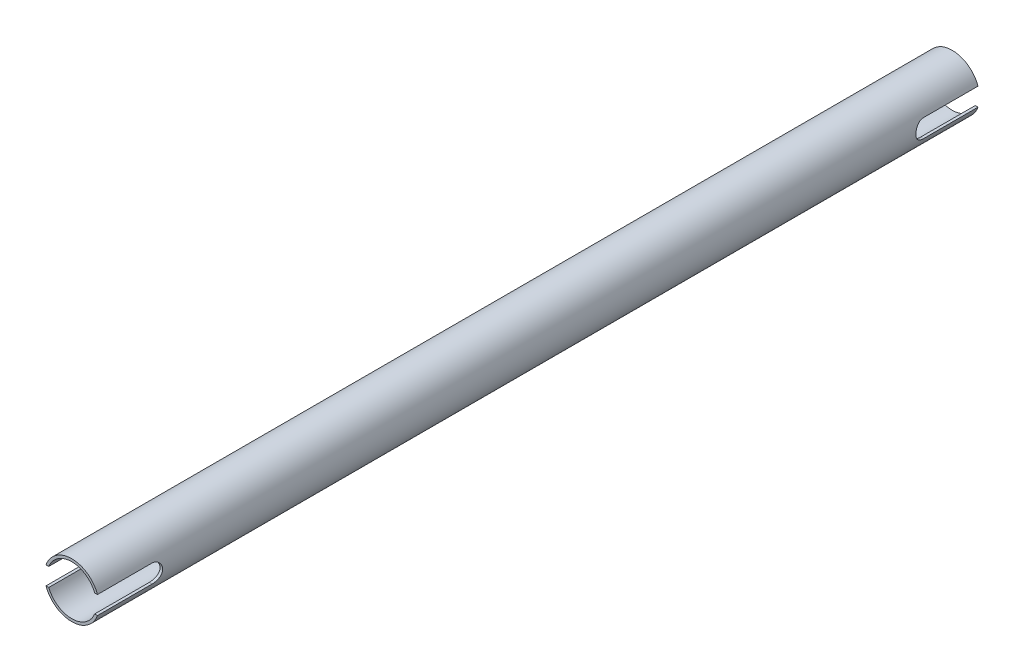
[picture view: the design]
ISO-10303-21;
HEADER;
FILE_DESCRIPTION(('STEP AP214'),'2;1');
FILE_NAME('part.step','',(''),(''),'','','');
FILE_SCHEMA(('AUTOMOTIVE_DESIGN { 1 0 10303 214 1 1 1 1 }'));
ENDSEC;
DATA;
#1=APPLICATION_CONTEXT('core data for automotive mechanical design processes');
#2=APPLICATION_PROTOCOL_DEFINITION('international standard','automotive_design',2000,#1);
#3=PRODUCT_CONTEXT('',#1,'mechanical');
#4=PRODUCT('Part','Part','',(#3));
#5=PRODUCT_RELATED_PRODUCT_CATEGORY('part','',(#4));
#6=PRODUCT_DEFINITION_FORMATION('','',#4);
#7=PRODUCT_DEFINITION_CONTEXT('part definition',#1,'design');
#8=PRODUCT_DEFINITION('design','',#6,#7);
#9=PRODUCT_DEFINITION_SHAPE('','',#8);
#10=(LENGTH_UNIT() NAMED_UNIT(*) SI_UNIT(.MILLI.,.METRE.));
#11=(NAMED_UNIT(*) PLANE_ANGLE_UNIT() SI_UNIT($,.RADIAN.));
#12=(NAMED_UNIT(*) SI_UNIT($,.STERADIAN.) SOLID_ANGLE_UNIT());
#13=UNCERTAINTY_MEASURE_WITH_UNIT(LENGTH_MEASURE(1.E-05),#10,'distance_accuracy_value','');
#14=(GEOMETRIC_REPRESENTATION_CONTEXT(3) GLOBAL_UNCERTAINTY_ASSIGNED_CONTEXT((#13)) GLOBAL_UNIT_ASSIGNED_CONTEXT((#10,
#11,#12)) REPRESENTATION_CONTEXT('',''));
#15=CARTESIAN_POINT('',(0.,0.,0.));
#16=DIRECTION('',(0.,0.,1.));
#17=DIRECTION('',(1.,0.,0.));
#18=AXIS2_PLACEMENT_3D('',#15,#16,#17);
#19=CARTESIAN_POINT('',(0.,0.,-153.697183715));
#20=DIRECTION('',(0.,0.,1.));
#21=DIRECTION('',(1.,0.,0.));
#22=AXIS2_PLACEMENT_3D('',#19,#20,#21);
#23=PLANE('',#22);
#24=DIRECTION('',(1.,0.,0.));
#25=VECTOR('',#24,1.);
#26=CARTESIAN_POINT('',(-9.525,3.17499999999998,-153.697183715));
#27=LINE('',#26,#25);
#28=CARTESIAN_POINT('',(-8.98025612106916,3.17499999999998,-153.697183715));
#29=VERTEX_POINT('',#28);
#30=CARTESIAN_POINT('',(-8.00659451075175,3.17499999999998,-153.697183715));
#31=VERTEX_POINT('',#30);
#32=EDGE_CURVE('E178',#29,#31,#27,.T.);
#33=ORIENTED_EDGE('',*,*,#32,.F.);
#34=CARTESIAN_POINT('',(0.,0.,-153.697183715));
#35=DIRECTION('',(0.,0.,1.));
#36=DIRECTION('',(1.,0.,0.));
#37=AXIS2_PLACEMENT_3D('',#34,#35,#36);
#38=CIRCLE('',#37,9.525);
#39=CARTESIAN_POINT('',(8.98025612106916,3.17499999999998,-153.697183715));
#40=VERTEX_POINT('',#39);
#41=EDGE_CURVE('E281',#40,#29,#38,.T.);
#42=ORIENTED_EDGE('',*,*,#41,.F.);
#43=CARTESIAN_POINT('',(8.00659451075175,3.17499999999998,-153.697183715));
#44=VERTEX_POINT('',#43);
#45=EDGE_CURVE('E344',#44,#40,#27,.T.);
#46=ORIENTED_EDGE('',*,*,#45,.F.);
#47=CARTESIAN_POINT('',(0.,0.,-153.697183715));
#48=DIRECTION('',(0.,0.,1.));
#49=DIRECTION('',(1.,0.,0.));
#50=AXIS2_PLACEMENT_3D('',#47,#48,#49);
#51=CIRCLE('',#50,8.61314);
#52=EDGE_CURVE('E272',#44,#31,#51,.T.);
#53=ORIENTED_EDGE('',*,*,#52,.T.);
#54=EDGE_LOOP('',(#33,#42,#46,#53));
#55=FACE_BOUND('',#54,.T.);
#56=ADVANCED_FACE('F40',(#55),#23,.F.);
#57=DIRECTION('',(1.,0.,0.));
#58=VECTOR('',#57,1.);
#59=CARTESIAN_POINT('',(-9.525,-3.17500000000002,-153.697183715));
#60=LINE('',#59,#58);
#61=CARTESIAN_POINT('',(8.00659451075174,-3.17500000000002,-153.697183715));
#62=VERTEX_POINT('',#61);
#63=CARTESIAN_POINT('',(8.98025612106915,-3.17500000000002,-153.697183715));
#64=VERTEX_POINT('',#63);
#65=EDGE_CURVE('E171',#62,#64,#60,.T.);
#66=ORIENTED_EDGE('',*,*,#65,.T.);
#67=CARTESIAN_POINT('',(-8.98025612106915,-3.17500000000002,-153.697183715));
#68=VERTEX_POINT('',#67);
#69=EDGE_CURVE('E279',#68,#64,#38,.T.);
#70=ORIENTED_EDGE('',*,*,#69,.F.);
#71=CARTESIAN_POINT('',(-8.00659451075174,-3.17500000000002,-153.697183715));
#72=VERTEX_POINT('',#71);
#73=EDGE_CURVE('E160',#68,#72,#60,.T.);
#74=ORIENTED_EDGE('',*,*,#73,.T.);
#75=EDGE_CURVE('E271',#72,#62,#51,.T.);
#76=ORIENTED_EDGE('',*,*,#75,.T.);
#77=EDGE_LOOP('',(#66,#70,#74,#76));
#78=FACE_BOUND('',#77,.T.);
#79=ADVANCED_FACE('F341',(#78),#23,.F.);
#80=CARTESIAN_POINT('',(0.,0.,153.697183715));
#81=DIRECTION('',(0.,0.,-1.));
#82=DIRECTION('',(-1.,0.,0.));
#83=AXIS2_PLACEMENT_3D('',#80,#81,#82);
#84=CYLINDRICAL_SURFACE('',#83,9.525);
#85=CARTESIAN_POINT('',(0.,0.,153.697183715));
#86=DIRECTION('',(0.,0.,1.));
#87=DIRECTION('',(1.,0.,0.));
#88=AXIS2_PLACEMENT_3D('',#85,#86,#87);
#89=CIRCLE('',#88,9.525);
#90=CARTESIAN_POINT('',(8.98025612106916,3.17499999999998,153.697183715));
#91=VERTEX_POINT('',#90);
#92=CARTESIAN_POINT('',(-8.98025612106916,3.17499999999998,153.697183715));
#93=VERTEX_POINT('',#92);
#94=EDGE_CURVE('E284',#91,#93,#89,.T.);
#95=ORIENTED_EDGE('',*,*,#94,.F.);
#96=DIRECTION('',(0.,0.,-1.));
#97=VECTOR('',#96,1.);
#98=CARTESIAN_POINT('',(8.98025612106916,3.17499999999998,153.697183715));
#99=LINE('',#98,#97);
#100=CARTESIAN_POINT('',(8.98025612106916,3.17499999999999,134.647183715));
#101=VERTEX_POINT('',#100);
#102=EDGE_CURVE('E268',#91,#101,#99,.T.);
#103=ORIENTED_EDGE('',*,*,#102,.T.);
#104=CARTESIAN_POINT('',(8.98025612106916,3.17499999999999,134.647183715));
#105=CARTESIAN_POINT('',(8.9802423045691,3.17501141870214,134.560560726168));
#106=CARTESIAN_POINT('',(8.98150913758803,3.17145526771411,134.473945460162));
#107=CARTESIAN_POINT('',(8.9865012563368,3.15729678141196,134.301386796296));
#108=CARTESIAN_POINT('',(8.99022587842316,3.14669634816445,134.215443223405));
#109=CARTESIAN_POINT('',(9.00001635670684,3.11857973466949,134.04508879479));
#110=CARTESIAN_POINT('',(9.00607526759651,3.1010840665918,133.96067416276));
#111=CARTESIAN_POINT('',(9.02033527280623,3.05935609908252,133.7937332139));
#112=CARTESIAN_POINT('',(9.02853644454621,3.03512355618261,133.711206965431));
#113=CARTESIAN_POINT('',(9.05598824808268,2.95264270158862,133.467402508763));
#114=CARTESIAN_POINT('',(9.07810279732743,2.8845689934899,133.309646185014));
#115=CARTESIAN_POINT('',(9.12745233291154,2.72437585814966,133.00777016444));
#116=CARTESIAN_POINT('',(9.15469046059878,2.63224166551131,132.863658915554));
#117=CARTESIAN_POINT('',(9.21240451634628,2.42269004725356,132.587506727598));
#118=CARTESIAN_POINT('',(9.24296080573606,2.30449481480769,132.456071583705));
#119=CARTESIAN_POINT('',(9.30318975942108,2.04783780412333,132.214476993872));
#120=CARTESIAN_POINT('',(9.33286226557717,1.90937242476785,132.104321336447));
#121=CARTESIAN_POINT('',(9.38891576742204,1.61164171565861,131.905636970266));
#122=CARTESIAN_POINT('',(9.41519063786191,1.4519278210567,131.817747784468));
#123=CARTESIAN_POINT('',(9.46053507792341,1.11896283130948,131.670328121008));
#124=CARTESIAN_POINT('',(9.47960684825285,0.945715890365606,131.610788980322));
#125=CARTESIAN_POINT('',(9.50782550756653,0.596993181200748,131.523822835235));
#126=CARTESIAN_POINT('',(9.5172945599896,0.421804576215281,131.49535084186));
#127=CARTESIAN_POINT('',(9.52638456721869,0.068894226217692,131.468004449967));
#128=CARTESIAN_POINT('',(9.52600786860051,-0.108826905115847,131.46912299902));
#129=CARTESIAN_POINT('',(9.515666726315,-0.454354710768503,131.500264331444));
#130=CARTESIAN_POINT('',(9.50607893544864,-0.622276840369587,131.529151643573));
#131=CARTESIAN_POINT('',(9.47886599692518,-0.950734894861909,131.613132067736));
#132=CARTESIAN_POINT('',(9.4612404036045,-1.11127040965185,131.668226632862));
#133=CARTESIAN_POINT('',(9.41945246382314,-1.42288461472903,131.803721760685));
#134=CARTESIAN_POINT('',(9.39520718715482,-1.57381114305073,131.884445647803));
#135=CARTESIAN_POINT('',(9.34270382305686,-1.86031043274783,132.068638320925));
#136=CARTESIAN_POINT('',(9.31444464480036,-1.99587900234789,132.172113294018));
#137=CARTESIAN_POINT('',(9.25532407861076,-2.25455959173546,132.404592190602));
#138=CARTESIAN_POINT('',(9.22440281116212,-2.37678676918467,132.534567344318));
#139=CARTESIAN_POINT('',(9.16455803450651,-2.59801162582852,132.813424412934));
#140=CARTESIAN_POINT('',(9.13563517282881,-2.697001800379,132.962312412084));
#141=CARTESIAN_POINT('',(9.08272269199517,-2.87021834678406,133.277785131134));
#142=CARTESIAN_POINT('',(9.05881220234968,-2.94405757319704,133.444598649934));
#143=CARTESIAN_POINT('',(9.02936653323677,-3.03267330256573,133.702816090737));
#144=CARTESIAN_POINT('',(9.02062228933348,-3.05851877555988,133.790205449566));
#145=CARTESIAN_POINT('',(9.00554368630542,-3.10263697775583,133.967067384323));
#146=CARTESIAN_POINT('',(8.99920822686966,-3.12091316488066,134.056538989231));
#147=CARTESIAN_POINT('',(8.989590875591,-3.14850521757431,134.229388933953));
#148=CARTESIAN_POINT('',(8.98609952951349,-3.15843785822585,134.312658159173));
#149=CARTESIAN_POINT('',(8.98142776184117,-3.1716856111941,134.479676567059));
#150=CARTESIAN_POINT('',(8.98024435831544,-3.17500926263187,134.563424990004));
#151=CARTESIAN_POINT('',(8.98025612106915,-3.17500000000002,134.647183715));
#152=B_SPLINE_CURVE_WITH_KNOTS('',3,(#104,#105,#106,#107,#108,#109,#110,#111,#112,#113,#114,
#115,#116,#117,#118,#119,#120,#121,#122,#123,#124,#125,#126,#127,#128,#129,#130,#131,#132,#133,
#134,#135,#136,#137,#138,#139,#140,#141,#142,#143,#144,#145,#146,#147,#148,#149,#150,#151),
.UNSPECIFIED.,.F.,.F.,(4,2,2,2,2,2,2,2,2,2,2,2,2,2,2,2,2,2,2,2,2,2,2,4),(0.,0.259773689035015,
0.519477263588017,0.77841402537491,1.03736014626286,1.55449291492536,2.07194378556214,
2.60766387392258,3.14347925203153,3.69327981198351,4.24291225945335,4.77342553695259,
5.30381237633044,5.81339512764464,6.32300613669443,6.83932018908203,7.35577482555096,
7.89650105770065,8.43740168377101,8.98628729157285,9.26063415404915,9.53485554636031,
9.78636405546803,10.0375473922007),.UNSPECIFIED.);
#153=CARTESIAN_POINT('',(8.98025612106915,-3.17500000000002,134.647183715));
#154=VERTEX_POINT('',#153);
#155=EDGE_CURVE('E258',#101,#154,#152,.T.);
#156=ORIENTED_EDGE('',*,*,#155,.T.);
#157=DIRECTION('',(0.,0.,-1.));
#158=VECTOR('',#157,1.);
#159=CARTESIAN_POINT('',(8.98025612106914,-3.17500000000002,153.697183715));
#160=LINE('',#159,#158);
#161=CARTESIAN_POINT('',(8.98025612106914,-3.17500000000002,153.697183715));
#162=VERTEX_POINT('',#161);
#163=EDGE_CURVE('E312',#154,#162,#160,.F.);
#164=ORIENTED_EDGE('',*,*,#163,.T.);
#165=CARTESIAN_POINT('',(-8.98025612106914,-3.17500000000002,153.697183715));
#166=VERTEX_POINT('',#165);
#167=EDGE_CURVE('E282',#166,#162,#89,.T.);
#168=ORIENTED_EDGE('',*,*,#167,.F.);
#169=DIRECTION('',(0.,0.,-1.));
#170=VECTOR('',#169,1.);
#171=CARTESIAN_POINT('',(-8.98025612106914,-3.17500000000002,153.697183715));
#172=LINE('',#171,#170);
#173=CARTESIAN_POINT('',(-8.98025612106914,-3.17500000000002,134.647183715));
#174=VERTEX_POINT('',#173);
#175=EDGE_CURVE('E259',#166,#174,#172,.T.);
#176=ORIENTED_EDGE('',*,*,#175,.T.);
#177=CARTESIAN_POINT('',(-8.98025612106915,-3.17500000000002,134.647183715));
#178=CARTESIAN_POINT('',(-8.98024230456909,-3.17501141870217,134.560560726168));
#179=CARTESIAN_POINT('',(-8.98150913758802,-3.17145526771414,134.473945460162));
#180=CARTESIAN_POINT('',(-8.98650125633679,-3.15729678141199,134.301386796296));
#181=CARTESIAN_POINT('',(-8.99022587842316,-3.14669634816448,134.215443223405));
#182=CARTESIAN_POINT('',(-9.00001635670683,-3.11857973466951,134.04508879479));
#183=CARTESIAN_POINT('',(-9.0060752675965,-3.10108406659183,133.96067416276));
#184=CARTESIAN_POINT('',(-9.02033527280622,-3.05935609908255,133.7937332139));
#185=CARTESIAN_POINT('',(-9.02853644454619,-3.03512355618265,133.711206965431));
#186=CARTESIAN_POINT('',(-9.05598824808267,-2.95264270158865,133.467402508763));
#187=CARTESIAN_POINT('',(-9.07810279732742,-2.88456899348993,133.309646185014));
#188=CARTESIAN_POINT('',(-9.12745233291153,-2.7243758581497,133.00777016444));
#189=CARTESIAN_POINT('',(-9.15469046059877,-2.63224166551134,132.863658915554));
#190=CARTESIAN_POINT('',(-9.21240451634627,-2.42269004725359,132.587506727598));
#191=CARTESIAN_POINT('',(-9.24296080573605,-2.30449481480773,132.456071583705));
#192=CARTESIAN_POINT('',(-9.30318975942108,-2.04783780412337,132.214476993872));
#193=CARTESIAN_POINT('',(-9.33286226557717,-1.90937242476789,132.104321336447));
#194=CARTESIAN_POINT('',(-9.38891576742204,-1.61164171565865,131.905636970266));
#195=CARTESIAN_POINT('',(-9.4151906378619,-1.45192782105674,131.817747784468));
#196=CARTESIAN_POINT('',(-9.46053507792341,-1.11896283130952,131.670328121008));
#197=CARTESIAN_POINT('',(-9.47960684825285,-0.945715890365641,131.610788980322));
#198=CARTESIAN_POINT('',(-9.50782550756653,-0.596993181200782,131.523822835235));
#199=CARTESIAN_POINT('',(-9.5172945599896,-0.421804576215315,131.49535084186));
#200=CARTESIAN_POINT('',(-9.52638456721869,-0.0688942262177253,131.468004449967));
#201=CARTESIAN_POINT('',(-9.52600786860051,0.108826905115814,131.46912299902));
#202=CARTESIAN_POINT('',(-9.51566672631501,0.45435471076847,131.500264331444));
#203=CARTESIAN_POINT('',(-9.50607893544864,0.622276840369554,131.529151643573));
#204=CARTESIAN_POINT('',(-9.47886599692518,0.950734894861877,131.613132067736));
#205=CARTESIAN_POINT('',(-9.4612404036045,1.11127040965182,131.668226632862));
#206=CARTESIAN_POINT('',(-9.41945246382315,1.422884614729,131.803721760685));
#207=CARTESIAN_POINT('',(-9.39520718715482,1.5738111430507,131.884445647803));
#208=CARTESIAN_POINT('',(-9.34270382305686,1.8603104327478,132.068638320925));
#209=CARTESIAN_POINT('',(-9.31444464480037,1.99587900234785,132.172113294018));
#210=CARTESIAN_POINT('',(-9.25532407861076,2.25455959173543,132.404592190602));
#211=CARTESIAN_POINT('',(-9.22440281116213,2.37678676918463,132.534567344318));
#212=CARTESIAN_POINT('',(-9.16455803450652,2.59801162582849,132.813424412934));
#213=CARTESIAN_POINT('',(-9.13563517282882,2.69700180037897,132.962312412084));
#214=CARTESIAN_POINT('',(-9.08272269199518,2.87021834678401,133.277785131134));
#215=CARTESIAN_POINT('',(-9.05881220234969,2.94405757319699,133.444598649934));
#216=CARTESIAN_POINT('',(-9.02936653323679,3.03267330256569,133.702816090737));
#217=CARTESIAN_POINT('',(-9.02062228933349,3.05851877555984,133.790205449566));
#218=CARTESIAN_POINT('',(-9.00554368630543,3.1026369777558,133.967067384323));
#219=CARTESIAN_POINT('',(-8.99920822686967,3.12091316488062,134.056538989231));
#220=CARTESIAN_POINT('',(-8.98959087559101,3.14850521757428,134.229388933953));
#221=CARTESIAN_POINT('',(-8.9860995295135,3.15843785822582,134.312658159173));
#222=CARTESIAN_POINT('',(-8.98142776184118,3.17168561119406,134.479676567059));
#223=CARTESIAN_POINT('',(-8.98024435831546,3.17500926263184,134.563424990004));
#224=CARTESIAN_POINT('',(-8.98025612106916,3.17499999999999,134.647183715));
#225=B_SPLINE_CURVE_WITH_KNOTS('',3,(#177,#178,#179,#180,#181,#182,#183,#184,#185,#186,#187,
#188,#189,#190,#191,#192,#193,#194,#195,#196,#197,#198,#199,#200,#201,#202,#203,#204,#205,#206,
#207,#208,#209,#210,#211,#212,#213,#214,#215,#216,#217,#218,#219,#220,#221,#222,#223,#224),
.UNSPECIFIED.,.F.,.F.,(4,2,2,2,2,2,2,2,2,2,2,2,2,2,2,2,2,2,2,2,2,2,2,4),(0.,0.259773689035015,
0.519477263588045,0.77841402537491,1.03736014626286,1.55449291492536,2.07194378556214,
2.60766387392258,3.14347925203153,3.69327981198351,4.24291225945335,4.7734255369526,
5.30381237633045,5.81339512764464,6.32300613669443,6.83932018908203,7.35577482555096,
7.89650105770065,8.43740168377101,8.98628729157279,9.26063415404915,9.53485554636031,
9.78636405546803,10.0375473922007),.UNSPECIFIED.);
#226=CARTESIAN_POINT('',(-8.98025612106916,3.17499999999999,134.647183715));
#227=VERTEX_POINT('',#226);
#228=EDGE_CURVE('E253',#174,#227,#225,.T.);
#229=ORIENTED_EDGE('',*,*,#228,.T.);
#230=DIRECTION('',(0.,0.,-1.));
#231=VECTOR('',#230,1.);
#232=CARTESIAN_POINT('',(-8.98025612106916,3.17499999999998,153.697183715));
#233=LINE('',#232,#231);
#234=EDGE_CURVE('E265',#227,#93,#233,.F.);
#235=ORIENTED_EDGE('',*,*,#234,.T.);
#236=EDGE_LOOP('',(#95,#103,#156,#164,#168,#176,#229,#235));
#237=FACE_BOUND('',#236,.T.);
#238=DIRECTION('',(0.,0.,-1.));
#239=VECTOR('',#238,1.);
#240=CARTESIAN_POINT('',(-8.98025612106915,-3.17500000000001,153.697183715));
#241=LINE('',#240,#239);
#242=CARTESIAN_POINT('',(-8.98025612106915,-3.17500000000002,-134.647183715));
#243=VERTEX_POINT('',#242);
#244=EDGE_CURVE('E154',#68,#243,#241,.F.);
#245=ORIENTED_EDGE('',*,*,#244,.F.);
#246=ORIENTED_EDGE('',*,*,#69,.T.);
#247=DIRECTION('',(0.,0.,-1.));
#248=VECTOR('',#247,1.);
#249=CARTESIAN_POINT('',(8.98025612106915,-3.17500000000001,153.697183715));
#250=LINE('',#249,#248);
#251=CARTESIAN_POINT('',(8.98025612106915,-3.17500000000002,-134.647183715));
#252=VERTEX_POINT('',#251);
#253=EDGE_CURVE('E165',#252,#64,#250,.T.);
#254=ORIENTED_EDGE('',*,*,#253,.F.);
#255=CARTESIAN_POINT('',(8.98025612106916,3.17499999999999,-134.647183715));
#256=CARTESIAN_POINT('',(8.9802423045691,3.17501141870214,-134.560560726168));
#257=CARTESIAN_POINT('',(8.98150913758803,3.17145526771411,-134.473945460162));
#258=CARTESIAN_POINT('',(8.9865012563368,3.15729678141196,-134.301386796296));
#259=CARTESIAN_POINT('',(8.99022587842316,3.14669634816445,-134.215443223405));
#260=CARTESIAN_POINT('',(9.00001635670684,3.11857973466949,-134.04508879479));
#261=CARTESIAN_POINT('',(9.00607526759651,3.1010840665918,-133.96067416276));
#262=CARTESIAN_POINT('',(9.02033527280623,3.05935609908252,-133.7937332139));
#263=CARTESIAN_POINT('',(9.02853644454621,3.03512355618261,-133.711206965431));
#264=CARTESIAN_POINT('',(9.05598824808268,2.95264270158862,-133.467402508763));
#265=CARTESIAN_POINT('',(9.07810279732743,2.8845689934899,-133.309646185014));
#266=CARTESIAN_POINT('',(9.12745233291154,2.72437585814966,-133.00777016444));
#267=CARTESIAN_POINT('',(9.15469046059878,2.63224166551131,-132.863658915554));
#268=CARTESIAN_POINT('',(9.21240451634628,2.42269004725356,-132.587506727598));
#269=CARTESIAN_POINT('',(9.24296080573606,2.30449481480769,-132.456071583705));
#270=CARTESIAN_POINT('',(9.30318975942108,2.04783780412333,-132.214476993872));
#271=CARTESIAN_POINT('',(9.33286226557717,1.90937242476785,-132.104321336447));
#272=CARTESIAN_POINT('',(9.38891576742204,1.61164171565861,-131.905636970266));
#273=CARTESIAN_POINT('',(9.41519063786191,1.4519278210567,-131.817747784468));
#274=CARTESIAN_POINT('',(9.46053507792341,1.11896283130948,-131.670328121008));
#275=CARTESIAN_POINT('',(9.47960684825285,0.945715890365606,-131.610788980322));
#276=CARTESIAN_POINT('',(9.50782550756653,0.596993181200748,-131.523822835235));
#277=CARTESIAN_POINT('',(9.5172945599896,0.421804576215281,-131.49535084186));
#278=CARTESIAN_POINT('',(9.52638456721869,0.068894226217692,-131.468004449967));
#279=CARTESIAN_POINT('',(9.52600786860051,-0.108826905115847,-131.46912299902));
#280=CARTESIAN_POINT('',(9.515666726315,-0.454354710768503,-131.500264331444));
#281=CARTESIAN_POINT('',(9.50607893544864,-0.622276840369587,-131.529151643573));
#282=CARTESIAN_POINT('',(9.47886599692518,-0.950734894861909,-131.613132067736));
#283=CARTESIAN_POINT('',(9.4612404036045,-1.11127040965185,-131.668226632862));
#284=CARTESIAN_POINT('',(9.41945246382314,-1.42288461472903,-131.803721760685));
#285=CARTESIAN_POINT('',(9.39520718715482,-1.57381114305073,-131.884445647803));
#286=CARTESIAN_POINT('',(9.34270382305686,-1.86031043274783,-132.068638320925));
#287=CARTESIAN_POINT('',(9.31444464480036,-1.99587900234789,-132.172113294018));
#288=CARTESIAN_POINT('',(9.25532407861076,-2.25455959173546,-132.404592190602));
#289=CARTESIAN_POINT('',(9.22440281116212,-2.37678676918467,-132.534567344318));
#290=CARTESIAN_POINT('',(9.16455803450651,-2.59801162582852,-132.813424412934));
#291=CARTESIAN_POINT('',(9.13563517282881,-2.697001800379,-132.962312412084));
#292=CARTESIAN_POINT('',(9.08272269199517,-2.87021834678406,-133.277785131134));
#293=CARTESIAN_POINT('',(9.05881220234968,-2.94405757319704,-133.444598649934));
#294=CARTESIAN_POINT('',(9.02936653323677,-3.03267330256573,-133.702816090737));
#295=CARTESIAN_POINT('',(9.02062228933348,-3.05851877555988,-133.790205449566));
#296=CARTESIAN_POINT('',(9.00554368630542,-3.10263697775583,-133.967067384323));
#297=CARTESIAN_POINT('',(8.99920822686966,-3.12091316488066,-134.056538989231));
#298=CARTESIAN_POINT('',(8.989590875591,-3.14850521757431,-134.229388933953));
#299=CARTESIAN_POINT('',(8.98609952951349,-3.15843785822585,-134.312658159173));
#300=CARTESIAN_POINT('',(8.98142776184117,-3.1716856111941,-134.479676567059));
#301=CARTESIAN_POINT('',(8.98024435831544,-3.17500926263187,-134.563424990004));
#302=CARTESIAN_POINT('',(8.98025612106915,-3.17500000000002,-134.647183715));
#303=B_SPLINE_CURVE_WITH_KNOTS('',3,(#255,#256,#257,#258,#259,#260,#261,#262,#263,#264,#265,
#266,#267,#268,#269,#270,#271,#272,#273,#274,#275,#276,#277,#278,#279,#280,#281,#282,#283,#284,
#285,#286,#287,#288,#289,#290,#291,#292,#293,#294,#295,#296,#297,#298,#299,#300,#301,#302),
.UNSPECIFIED.,.F.,.F.,(4,2,2,2,2,2,2,2,2,2,2,2,2,2,2,2,2,2,2,2,2,2,2,4),(0.,0.259773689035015,
0.519477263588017,0.77841402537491,1.03736014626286,1.55449291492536,2.07194378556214,
2.60766387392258,3.14347925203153,3.69327981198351,4.24291225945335,4.77342553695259,
5.30381237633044,5.81339512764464,6.32300613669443,6.83932018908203,7.35577482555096,
7.89650105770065,8.43740168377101,8.98628729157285,9.26063415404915,9.53485554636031,
9.78636405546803,10.0375473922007),.UNSPECIFIED.);
#304=CARTESIAN_POINT('',(8.98025612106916,3.17499999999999,-134.647183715));
#305=VERTEX_POINT('',#304);
#306=EDGE_CURVE('E176',#305,#252,#303,.T.);
#307=ORIENTED_EDGE('',*,*,#306,.F.);
#308=DIRECTION('',(0.,0.,-1.));
#309=VECTOR('',#308,1.);
#310=CARTESIAN_POINT('',(8.98025612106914,3.17500000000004,153.697183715));
#311=LINE('',#310,#309);
#312=EDGE_CURVE('E327',#40,#305,#311,.F.);
#313=ORIENTED_EDGE('',*,*,#312,.F.);
#314=ORIENTED_EDGE('',*,*,#41,.T.);
#315=DIRECTION('',(0.,0.,-1.));
#316=VECTOR('',#315,1.);
#317=CARTESIAN_POINT('',(-8.98025612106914,3.17500000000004,153.697183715));
#318=LINE('',#317,#316);
#319=CARTESIAN_POINT('',(-8.98025612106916,3.17499999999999,-134.647183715));
#320=VERTEX_POINT('',#319);
#321=EDGE_CURVE('E175',#320,#29,#318,.T.);
#322=ORIENTED_EDGE('',*,*,#321,.F.);
#323=CARTESIAN_POINT('',(-8.98025612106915,-3.17500000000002,-134.647183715));
#324=CARTESIAN_POINT('',(-8.98024230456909,-3.17501141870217,-134.560560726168));
#325=CARTESIAN_POINT('',(-8.98150913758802,-3.17145526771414,-134.473945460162));
#326=CARTESIAN_POINT('',(-8.98650125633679,-3.15729678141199,-134.301386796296));
#327=CARTESIAN_POINT('',(-8.99022587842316,-3.14669634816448,-134.215443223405));
#328=CARTESIAN_POINT('',(-9.00001635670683,-3.11857973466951,-134.04508879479));
#329=CARTESIAN_POINT('',(-9.0060752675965,-3.10108406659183,-133.96067416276));
#330=CARTESIAN_POINT('',(-9.02033527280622,-3.05935609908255,-133.7937332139));
#331=CARTESIAN_POINT('',(-9.02853644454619,-3.03512355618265,-133.711206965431));
#332=CARTESIAN_POINT('',(-9.05598824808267,-2.95264270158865,-133.467402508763));
#333=CARTESIAN_POINT('',(-9.07810279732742,-2.88456899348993,-133.309646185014));
#334=CARTESIAN_POINT('',(-9.12745233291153,-2.7243758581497,-133.00777016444));
#335=CARTESIAN_POINT('',(-9.15469046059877,-2.63224166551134,-132.863658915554));
#336=CARTESIAN_POINT('',(-9.21240451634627,-2.42269004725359,-132.587506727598));
#337=CARTESIAN_POINT('',(-9.24296080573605,-2.30449481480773,-132.456071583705));
#338=CARTESIAN_POINT('',(-9.30318975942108,-2.04783780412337,-132.214476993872));
#339=CARTESIAN_POINT('',(-9.33286226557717,-1.90937242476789,-132.104321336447));
#340=CARTESIAN_POINT('',(-9.38891576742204,-1.61164171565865,-131.905636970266));
#341=CARTESIAN_POINT('',(-9.4151906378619,-1.45192782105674,-131.817747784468));
#342=CARTESIAN_POINT('',(-9.46053507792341,-1.11896283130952,-131.670328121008));
#343=CARTESIAN_POINT('',(-9.47960684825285,-0.945715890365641,-131.610788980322));
#344=CARTESIAN_POINT('',(-9.50782550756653,-0.596993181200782,-131.523822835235));
#345=CARTESIAN_POINT('',(-9.5172945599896,-0.421804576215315,-131.49535084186));
#346=CARTESIAN_POINT('',(-9.52638456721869,-0.0688942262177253,-131.468004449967));
#347=CARTESIAN_POINT('',(-9.52600786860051,0.108826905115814,-131.46912299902));
#348=CARTESIAN_POINT('',(-9.51566672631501,0.45435471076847,-131.500264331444));
#349=CARTESIAN_POINT('',(-9.50607893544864,0.622276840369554,-131.529151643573));
#350=CARTESIAN_POINT('',(-9.47886599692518,0.950734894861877,-131.613132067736));
#351=CARTESIAN_POINT('',(-9.4612404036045,1.11127040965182,-131.668226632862));
#352=CARTESIAN_POINT('',(-9.41945246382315,1.422884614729,-131.803721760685));
#353=CARTESIAN_POINT('',(-9.39520718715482,1.5738111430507,-131.884445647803));
#354=CARTESIAN_POINT('',(-9.34270382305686,1.8603104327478,-132.068638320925));
#355=CARTESIAN_POINT('',(-9.31444464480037,1.99587900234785,-132.172113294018));
#356=CARTESIAN_POINT('',(-9.25532407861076,2.25455959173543,-132.404592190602));
#357=CARTESIAN_POINT('',(-9.22440281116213,2.37678676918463,-132.534567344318));
#358=CARTESIAN_POINT('',(-9.16455803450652,2.59801162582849,-132.813424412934));
#359=CARTESIAN_POINT('',(-9.13563517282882,2.69700180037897,-132.962312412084));
#360=CARTESIAN_POINT('',(-9.08272269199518,2.87021834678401,-133.277785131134));
#361=CARTESIAN_POINT('',(-9.05881220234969,2.94405757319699,-133.444598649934));
#362=CARTESIAN_POINT('',(-9.02936653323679,3.03267330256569,-133.702816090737));
#363=CARTESIAN_POINT('',(-9.02062228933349,3.05851877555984,-133.790205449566));
#364=CARTESIAN_POINT('',(-9.00554368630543,3.1026369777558,-133.967067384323));
#365=CARTESIAN_POINT('',(-8.99920822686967,3.12091316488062,-134.056538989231));
#366=CARTESIAN_POINT('',(-8.98959087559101,3.14850521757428,-134.229388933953));
#367=CARTESIAN_POINT('',(-8.9860995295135,3.15843785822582,-134.312658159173));
#368=CARTESIAN_POINT('',(-8.98142776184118,3.17168561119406,-134.479676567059));
#369=CARTESIAN_POINT('',(-8.98024435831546,3.17500926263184,-134.563424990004));
#370=CARTESIAN_POINT('',(-8.98025612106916,3.17499999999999,-134.647183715));
#371=B_SPLINE_CURVE_WITH_KNOTS('',3,(#323,#324,#325,#326,#327,#328,#329,#330,#331,#332,#333,
#334,#335,#336,#337,#338,#339,#340,#341,#342,#343,#344,#345,#346,#347,#348,#349,#350,#351,#352,
#353,#354,#355,#356,#357,#358,#359,#360,#361,#362,#363,#364,#365,#366,#367,#368,#369,#370),
.UNSPECIFIED.,.F.,.F.,(4,2,2,2,2,2,2,2,2,2,2,2,2,2,2,2,2,2,2,2,2,2,2,4),(0.,0.259773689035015,
0.519477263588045,0.77841402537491,1.03736014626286,1.55449291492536,2.07194378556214,
2.60766387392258,3.14347925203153,3.69327981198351,4.24291225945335,4.7734255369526,
5.30381237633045,5.81339512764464,6.32300613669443,6.83932018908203,7.35577482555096,
7.89650105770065,8.43740168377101,8.98628729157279,9.26063415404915,9.53485554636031,
9.78636405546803,10.0375473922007),.UNSPECIFIED.);
#372=EDGE_CURVE('E166',#243,#320,#371,.T.);
#373=ORIENTED_EDGE('',*,*,#372,.F.);
#374=EDGE_LOOP('',(#245,#246,#254,#307,#313,#314,#322,#373));
#375=FACE_BOUND('',#374,.T.);
#376=ADVANCED_FACE('F42',(#237,#375),#84,.T.);
#377=CARTESIAN_POINT('',(0.,0.,153.697183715));
#378=DIRECTION('',(0.,0.,-1.));
#379=DIRECTION('',(-1.,0.,0.));
#380=AXIS2_PLACEMENT_3D('',#377,#378,#379);
#381=CYLINDRICAL_SURFACE('',#380,8.61314);
#382=DIRECTION('',(0.,0.,-1.));
#383=VECTOR('',#382,1.);
#384=CARTESIAN_POINT('',(-8.00659451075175,3.17499999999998,153.697183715));
#385=LINE('',#384,#383);
#386=CARTESIAN_POINT('',(-8.00659451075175,3.17499999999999,134.647183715));
#387=VERTEX_POINT('',#386);
#388=CARTESIAN_POINT('',(-8.00659451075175,3.17499999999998,153.697183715));
#389=VERTEX_POINT('',#388);
#390=EDGE_CURVE('E239',#387,#389,#385,.F.);
#391=ORIENTED_EDGE('',*,*,#390,.F.);
#392=CARTESIAN_POINT('',(-8.00659451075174,-3.17500000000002,134.647183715));
#393=CARTESIAN_POINT('',(-8.00657879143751,-3.17501205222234,134.561169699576));
#394=CARTESIAN_POINT('',(-8.00798019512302,-3.17150498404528,134.475164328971));
#395=CARTESIAN_POINT('',(-8.01350001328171,-3.15754665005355,134.303833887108));
#396=CARTESIAN_POINT('',(-8.01761754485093,-3.14709764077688,134.218508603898));
#397=CARTESIAN_POINT('',(-8.02843384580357,-3.11939719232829,134.049436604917));
#398=CARTESIAN_POINT('',(-8.03512366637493,-3.10216933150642,133.965685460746));
#399=CARTESIAN_POINT('',(-8.05086033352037,-3.06109615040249,133.800068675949));
#400=CARTESIAN_POINT('',(-8.05990729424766,-3.03725050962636,133.718203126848));
#401=CARTESIAN_POINT('',(-8.09016839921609,-2.95613292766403,133.476403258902));
#402=CARTESIAN_POINT('',(-8.11452302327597,-2.88923159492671,133.319972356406));
#403=CARTESIAN_POINT('',(-8.16883258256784,-2.73189398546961,133.02050825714));
#404=CARTESIAN_POINT('',(-8.19879191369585,-2.64143921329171,132.877485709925));
#405=CARTESIAN_POINT('',(-8.26253332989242,-2.43492887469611,132.602037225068));
#406=CARTESIAN_POINT('',(-8.29642486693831,-2.31793297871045,132.470340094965));
#407=CARTESIAN_POINT('',(-8.36329714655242,-2.06366320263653,132.227929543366));
#408=CARTESIAN_POINT('',(-8.39627771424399,-1.9263854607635,132.117220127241));
#409=CARTESIAN_POINT('',(-8.45891569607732,-1.629904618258,131.916412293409));
#410=CARTESIAN_POINT('',(-8.48842893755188,-1.4701307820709,131.827107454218));
#411=CARTESIAN_POINT('',(-8.53948707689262,-1.13655272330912,131.676949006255));
#412=CARTESIAN_POINT('',(-8.56103485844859,-0.962753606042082,131.616085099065));
#413=CARTESIAN_POINT('',(-8.59295493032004,-0.613765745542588,131.52709172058));
#414=CARTESIAN_POINT('',(-8.60375681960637,-0.438938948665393,131.497699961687));
#415=CARTESIAN_POINT('',(-8.61450719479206,-0.0865198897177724,131.468445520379));
#416=CARTESIAN_POINT('',(-8.61445889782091,0.0910715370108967,131.468574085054));
#417=CARTESIAN_POINT('',(-8.60379005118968,0.434944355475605,131.497612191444));
#418=CARTESIAN_POINT('',(-8.59367530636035,0.601360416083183,131.525144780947));
#419=CARTESIAN_POINT('',(-8.56466915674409,0.927017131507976,131.605898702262));
#420=CARTESIAN_POINT('',(-8.54577725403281,1.08625737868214,131.659121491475));
#421=CARTESIAN_POINT('',(-8.50075667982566,1.3957597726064,131.790410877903));
#422=CARTESIAN_POINT('',(-8.47452782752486,1.5458598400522,131.868823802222));
#423=CARTESIAN_POINT('',(-8.41749996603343,1.83113878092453,132.047962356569));
#424=CARTESIAN_POINT('',(-8.38669950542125,1.966312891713,132.148695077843));
#425=CARTESIAN_POINT('',(-8.32165508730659,2.22602120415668,132.376298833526));
#426=CARTESIAN_POINT('',(-8.28731490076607,2.34951911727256,132.504327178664));
#427=CARTESIAN_POINT('',(-8.22046423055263,2.573686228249,132.779485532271));
#428=CARTESIAN_POINT('',(-8.18795444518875,2.67434675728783,132.926622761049));
#429=CARTESIAN_POINT('',(-8.12783577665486,2.85192851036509,133.23999905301));
#430=CARTESIAN_POINT('',(-8.10034614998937,2.92829789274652,133.406578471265));
#431=CARTESIAN_POINT('',(-8.06616055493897,3.02064378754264,133.664975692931));
#432=CARTESIAN_POINT('',(-8.05594153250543,3.04772112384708,133.752510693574));
#433=CARTESIAN_POINT('',(-8.03818255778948,3.0942567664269,133.929837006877));
#434=CARTESIAN_POINT('',(-8.03064139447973,3.11371851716,134.019627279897));
#435=CARTESIAN_POINT('',(-8.01865729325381,3.14445483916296,134.198742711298));
#436=CARTESIAN_POINT('',(-8.01414947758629,3.15590108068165,134.288034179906));
#437=CARTESIAN_POINT('',(-8.00811024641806,3.17117692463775,134.467274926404));
#438=CARTESIAN_POINT('',(-8.00657586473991,3.17501411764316,134.557223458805));
#439=CARTESIAN_POINT('',(-8.00659451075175,3.17499999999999,134.647183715));
#440=B_SPLINE_CURVE_WITH_KNOTS('',3,(#392,#393,#394,#395,#396,#397,#398,#399,#400,#401,#402,
#403,#404,#405,#406,#407,#408,#409,#410,#411,#412,#413,#414,#415,#416,#417,#418,#419,#420,#421,
#422,#423,#424,#425,#426,#427,#428,#429,#430,#431,#432,#433,#434,#435,#436,#437,#438,#439),
.UNSPECIFIED.,.F.,.F.,(4,2,2,2,2,2,2,2,2,2,2,2,2,2,2,2,2,2,2,2,2,2,2,4),(0.,0.257944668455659,
0.515805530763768,0.772777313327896,1.0297615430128,1.54284702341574,2.05633662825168,
2.59210103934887,3.1279675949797,3.68138042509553,4.23459270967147,4.76467407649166,
5.29459827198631,5.79917501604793,6.30378038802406,6.81564369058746,7.32766985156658,
7.86869704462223,8.40992926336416,8.96269988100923,9.23897231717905,9.51511965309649,
9.78515512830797,10.0549210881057),.UNSPECIFIED.);
#441=CARTESIAN_POINT('',(-8.00659451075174,-3.17500000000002,134.647183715));
#442=VERTEX_POINT('',#441);
#443=EDGE_CURVE('E234',#442,#387,#440,.T.);
#444=ORIENTED_EDGE('',*,*,#443,.F.);
#445=DIRECTION('',(0.,0.,-1.));
#446=VECTOR('',#445,1.);
#447=CARTESIAN_POINT('',(-8.00659451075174,-3.17500000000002,153.697183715));
#448=LINE('',#447,#446);
#449=CARTESIAN_POINT('',(-8.00659451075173,-3.17500000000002,153.697183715));
#450=VERTEX_POINT('',#449);
#451=EDGE_CURVE('E240',#450,#442,#448,.T.);
#452=ORIENTED_EDGE('',*,*,#451,.F.);
#453=CARTESIAN_POINT('',(0.,0.,153.697183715));
#454=DIRECTION('',(0.,0.,1.));
#455=DIRECTION('',(1.,0.,0.));
#456=AXIS2_PLACEMENT_3D('',#453,#454,#455);
#457=CIRCLE('',#456,8.61314);
#458=CARTESIAN_POINT('',(8.00659451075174,-3.17500000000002,153.697183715));
#459=VERTEX_POINT('',#458);
#460=EDGE_CURVE('E275',#450,#459,#457,.T.);
#461=ORIENTED_EDGE('',*,*,#460,.T.);
#462=DIRECTION('',(0.,0.,-1.));
#463=VECTOR('',#462,1.);
#464=CARTESIAN_POINT('',(8.00659451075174,-3.17500000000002,153.697183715));
#465=LINE('',#464,#463);
#466=CARTESIAN_POINT('',(8.00659451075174,-3.17500000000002,134.647183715));
#467=VERTEX_POINT('',#466);
#468=EDGE_CURVE('E285',#467,#459,#465,.F.);
#469=ORIENTED_EDGE('',*,*,#468,.F.);
#470=CARTESIAN_POINT('',(8.00659451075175,3.17499999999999,134.647183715));
#471=CARTESIAN_POINT('',(8.00657879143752,3.17501205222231,134.561169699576));
#472=CARTESIAN_POINT('',(8.00798019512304,3.17150498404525,134.475164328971));
#473=CARTESIAN_POINT('',(8.01350001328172,3.15754665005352,134.303833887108));
#474=CARTESIAN_POINT('',(8.01761754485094,3.14709764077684,134.218508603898));
#475=CARTESIAN_POINT('',(8.02843384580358,3.11939719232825,134.049436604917));
#476=CARTESIAN_POINT('',(8.03512366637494,3.10216933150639,133.965685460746));
#477=CARTESIAN_POINT('',(8.05086033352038,3.06109615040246,133.800068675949));
#478=CARTESIAN_POINT('',(8.05990729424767,3.03725050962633,133.718203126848));
#479=CARTESIAN_POINT('',(8.0901683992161,2.956132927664,133.476403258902));
#480=CARTESIAN_POINT('',(8.11452302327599,2.88923159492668,133.319972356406));
#481=CARTESIAN_POINT('',(8.16883258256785,2.73189398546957,133.02050825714));
#482=CARTESIAN_POINT('',(8.19879191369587,2.64143921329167,132.877485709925));
#483=CARTESIAN_POINT('',(8.26253332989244,2.43492887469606,132.602037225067));
#484=CARTESIAN_POINT('',(8.29642486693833,2.3179329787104,132.470340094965));
#485=CARTESIAN_POINT('',(8.36329714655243,2.06366320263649,132.227929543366));
#486=CARTESIAN_POINT('',(8.396277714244,1.92638546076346,132.117220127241));
#487=CARTESIAN_POINT('',(8.45891569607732,1.62990461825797,131.916412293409));
#488=CARTESIAN_POINT('',(8.48842893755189,1.47013078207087,131.827107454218));
#489=CARTESIAN_POINT('',(8.53948707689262,1.13655272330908,131.676949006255));
#490=CARTESIAN_POINT('',(8.56103485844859,0.962753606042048,131.616085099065));
#491=CARTESIAN_POINT('',(8.59295493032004,0.613765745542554,131.52709172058));
#492=CARTESIAN_POINT('',(8.60375681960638,0.43893894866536,131.497699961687));
#493=CARTESIAN_POINT('',(8.61450719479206,0.0865198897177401,131.468445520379));
#494=CARTESIAN_POINT('',(8.61445889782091,-0.0910715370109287,131.468574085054));
#495=CARTESIAN_POINT('',(8.60379005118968,-0.434944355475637,131.497612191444));
#496=CARTESIAN_POINT('',(8.59367530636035,-0.601360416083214,131.525144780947));
#497=CARTESIAN_POINT('',(8.56466915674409,-0.927017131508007,131.605898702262));
#498=CARTESIAN_POINT('',(8.5457772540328,-1.08625737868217,131.659121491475));
#499=CARTESIAN_POINT('',(8.50075667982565,-1.39575977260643,131.790410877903));
#500=CARTESIAN_POINT('',(8.47452782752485,-1.54585984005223,131.868823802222));
#501=CARTESIAN_POINT('',(8.41749996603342,-1.83113878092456,132.047962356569));
#502=CARTESIAN_POINT('',(8.38669950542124,-1.96631289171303,132.148695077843));
#503=CARTESIAN_POINT('',(8.32165508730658,-2.22602120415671,132.376298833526));
#504=CARTESIAN_POINT('',(8.28731490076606,-2.3495191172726,132.504327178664));
#505=CARTESIAN_POINT('',(8.22046423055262,-2.57368622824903,132.779485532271));
#506=CARTESIAN_POINT('',(8.18795444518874,-2.67434675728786,132.926622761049));
#507=CARTESIAN_POINT('',(8.12783577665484,-2.85192851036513,133.23999905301));
#508=CARTESIAN_POINT('',(8.10034614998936,-2.92829789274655,133.406578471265));
#509=CARTESIAN_POINT('',(8.06616055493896,-3.02064378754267,133.664975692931));
#510=CARTESIAN_POINT('',(8.05594153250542,-3.04772112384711,133.752510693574));
#511=CARTESIAN_POINT('',(8.03818255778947,-3.09425676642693,133.929837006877));
#512=CARTESIAN_POINT('',(8.03064139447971,-3.11371851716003,134.019627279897));
#513=CARTESIAN_POINT('',(8.0186572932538,-3.144454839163,134.198742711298));
#514=CARTESIAN_POINT('',(8.01414947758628,-3.15590108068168,134.288034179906));
#515=CARTESIAN_POINT('',(8.00811024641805,-3.17117692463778,134.467274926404));
#516=CARTESIAN_POINT('',(8.0065758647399,-3.17501411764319,134.557223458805));
#517=CARTESIAN_POINT('',(8.00659451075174,-3.17500000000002,134.647183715));
#518=B_SPLINE_CURVE_WITH_KNOTS('',3,(#470,#471,#472,#473,#474,#475,#476,#477,#478,#479,#480,
#481,#482,#483,#484,#485,#486,#487,#488,#489,#490,#491,#492,#493,#494,#495,#496,#497,#498,#499,
#500,#501,#502,#503,#504,#505,#506,#507,#508,#509,#510,#511,#512,#513,#514,#515,#516,#517),
.UNSPECIFIED.,.F.,.F.,(4,2,2,2,2,2,2,2,2,2,2,2,2,2,2,2,2,2,2,2,2,2,2,4),(0.,0.257944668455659,
0.515805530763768,0.772777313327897,1.0297615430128,1.54284702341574,2.05633662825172,
2.59210103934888,3.1279675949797,3.68138042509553,4.23459270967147,4.76467407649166,
5.29459827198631,5.79917501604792,6.30378038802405,6.81564369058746,7.32766985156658,
7.86869704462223,8.40992926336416,8.96269988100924,9.23897231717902,9.51511965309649,
9.78515512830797,10.0549210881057),.UNSPECIFIED.);
#519=CARTESIAN_POINT('',(8.00659451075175,3.17499999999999,134.647183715));
#520=VERTEX_POINT('',#519);
#521=EDGE_CURVE('E226',#520,#467,#518,.T.);
#522=ORIENTED_EDGE('',*,*,#521,.F.);
#523=DIRECTION('',(0.,0.,-1.));
#524=VECTOR('',#523,1.);
#525=CARTESIAN_POINT('',(8.00659451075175,3.17499999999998,153.697183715));
#526=LINE('',#525,#524);
#527=CARTESIAN_POINT('',(8.00659451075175,3.17499999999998,153.697183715));
#528=VERTEX_POINT('',#527);
#529=EDGE_CURVE('E290',#528,#520,#526,.T.);
#530=ORIENTED_EDGE('',*,*,#529,.F.);
#531=EDGE_CURVE('E276',#528,#389,#457,.T.);
#532=ORIENTED_EDGE('',*,*,#531,.T.);
#533=EDGE_LOOP('',(#391,#444,#452,#461,#469,#522,#530,#532));
#534=FACE_BOUND('',#533,.T.);
#535=CARTESIAN_POINT('',(-8.00659451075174,-3.17500000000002,-134.647183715));
#536=CARTESIAN_POINT('',(-8.00657879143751,-3.17501205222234,-134.561169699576));
#537=CARTESIAN_POINT('',(-8.00798019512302,-3.17150498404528,-134.475164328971));
#538=CARTESIAN_POINT('',(-8.01350001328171,-3.15754665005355,-134.303833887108));
#539=CARTESIAN_POINT('',(-8.01761754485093,-3.14709764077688,-134.218508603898));
#540=CARTESIAN_POINT('',(-8.02843384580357,-3.11939719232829,-134.049436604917));
#541=CARTESIAN_POINT('',(-8.03512366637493,-3.10216933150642,-133.965685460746));
#542=CARTESIAN_POINT('',(-8.05086033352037,-3.06109615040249,-133.800068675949));
#543=CARTESIAN_POINT('',(-8.05990729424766,-3.03725050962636,-133.718203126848));
#544=CARTESIAN_POINT('',(-8.09016839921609,-2.95613292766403,-133.476403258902));
#545=CARTESIAN_POINT('',(-8.11452302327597,-2.88923159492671,-133.319972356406));
#546=CARTESIAN_POINT('',(-8.16883258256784,-2.73189398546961,-133.02050825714));
#547=CARTESIAN_POINT('',(-8.19879191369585,-2.64143921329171,-132.877485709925));
#548=CARTESIAN_POINT('',(-8.26253332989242,-2.43492887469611,-132.602037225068));
#549=CARTESIAN_POINT('',(-8.29642486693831,-2.31793297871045,-132.470340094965));
#550=CARTESIAN_POINT('',(-8.36329714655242,-2.06366320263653,-132.227929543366));
#551=CARTESIAN_POINT('',(-8.39627771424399,-1.9263854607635,-132.117220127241));
#552=CARTESIAN_POINT('',(-8.45891569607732,-1.629904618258,-131.916412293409));
#553=CARTESIAN_POINT('',(-8.48842893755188,-1.4701307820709,-131.827107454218));
#554=CARTESIAN_POINT('',(-8.53948707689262,-1.13655272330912,-131.676949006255));
#555=CARTESIAN_POINT('',(-8.56103485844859,-0.962753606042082,-131.616085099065));
#556=CARTESIAN_POINT('',(-8.59295493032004,-0.613765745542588,-131.52709172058));
#557=CARTESIAN_POINT('',(-8.60375681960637,-0.438938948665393,-131.497699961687));
#558=CARTESIAN_POINT('',(-8.61450719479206,-0.0865198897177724,-131.468445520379));
#559=CARTESIAN_POINT('',(-8.61445889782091,0.0910715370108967,-131.468574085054));
#560=CARTESIAN_POINT('',(-8.60379005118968,0.434944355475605,-131.497612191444));
#561=CARTESIAN_POINT('',(-8.59367530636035,0.601360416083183,-131.525144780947));
#562=CARTESIAN_POINT('',(-8.56466915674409,0.927017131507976,-131.605898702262));
#563=CARTESIAN_POINT('',(-8.54577725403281,1.08625737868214,-131.659121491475));
#564=CARTESIAN_POINT('',(-8.50075667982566,1.3957597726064,-131.790410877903));
#565=CARTESIAN_POINT('',(-8.47452782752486,1.5458598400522,-131.868823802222));
#566=CARTESIAN_POINT('',(-8.41749996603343,1.83113878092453,-132.047962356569));
#567=CARTESIAN_POINT('',(-8.38669950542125,1.966312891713,-132.148695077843));
#568=CARTESIAN_POINT('',(-8.32165508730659,2.22602120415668,-132.376298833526));
#569=CARTESIAN_POINT('',(-8.28731490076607,2.34951911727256,-132.504327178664));
#570=CARTESIAN_POINT('',(-8.22046423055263,2.573686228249,-132.779485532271));
#571=CARTESIAN_POINT('',(-8.18795444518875,2.67434675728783,-132.926622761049));
#572=CARTESIAN_POINT('',(-8.12783577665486,2.85192851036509,-133.23999905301));
#573=CARTESIAN_POINT('',(-8.10034614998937,2.92829789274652,-133.406578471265));
#574=CARTESIAN_POINT('',(-8.06616055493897,3.02064378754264,-133.664975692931));
#575=CARTESIAN_POINT('',(-8.05594153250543,3.04772112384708,-133.752510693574));
#576=CARTESIAN_POINT('',(-8.03818255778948,3.0942567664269,-133.929837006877));
#577=CARTESIAN_POINT('',(-8.03064139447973,3.11371851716,-134.019627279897));
#578=CARTESIAN_POINT('',(-8.01865729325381,3.14445483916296,-134.198742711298));
#579=CARTESIAN_POINT('',(-8.01414947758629,3.15590108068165,-134.288034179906));
#580=CARTESIAN_POINT('',(-8.00811024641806,3.17117692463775,-134.467274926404));
#581=CARTESIAN_POINT('',(-8.00657586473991,3.17501411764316,-134.557223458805));
#582=CARTESIAN_POINT('',(-8.00659451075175,3.17499999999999,-134.647183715));
#583=B_SPLINE_CURVE_WITH_KNOTS('',3,(#535,#536,#537,#538,#539,#540,#541,#542,#543,#544,#545,
#546,#547,#548,#549,#550,#551,#552,#553,#554,#555,#556,#557,#558,#559,#560,#561,#562,#563,#564,
#565,#566,#567,#568,#569,#570,#571,#572,#573,#574,#575,#576,#577,#578,#579,#580,#581,#582),
.UNSPECIFIED.,.F.,.F.,(4,2,2,2,2,2,2,2,2,2,2,2,2,2,2,2,2,2,2,2,2,2,2,4),(0.,0.257944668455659,
0.515805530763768,0.772777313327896,1.0297615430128,1.54284702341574,2.05633662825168,
2.59210103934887,3.1279675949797,3.68138042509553,4.23459270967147,4.76467407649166,
5.29459827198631,5.79917501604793,6.30378038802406,6.81564369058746,7.32766985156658,
7.86869704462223,8.40992926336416,8.96269988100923,9.23897231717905,9.51511965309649,
9.78515512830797,10.0549210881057),.UNSPECIFIED.);
#584=CARTESIAN_POINT('',(-8.00659451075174,-3.17500000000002,-134.647183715));
#585=VERTEX_POINT('',#584);
#586=CARTESIAN_POINT('',(-8.00659451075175,3.17499999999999,-134.647183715));
#587=VERTEX_POINT('',#586);
#588=EDGE_CURVE('E170',#585,#587,#583,.T.);
#589=ORIENTED_EDGE('',*,*,#588,.T.);
#590=DIRECTION('',(0.,0.,-1.));
#591=VECTOR('',#590,1.);
#592=CARTESIAN_POINT('',(-8.00659451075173,3.17500000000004,153.697183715));
#593=LINE('',#592,#591);
#594=EDGE_CURVE('E12',#587,#31,#593,.T.);
#595=ORIENTED_EDGE('',*,*,#594,.T.);
#596=ORIENTED_EDGE('',*,*,#52,.F.);
#597=DIRECTION('',(0.,0.,-1.));
#598=VECTOR('',#597,1.);
#599=CARTESIAN_POINT('',(8.00659451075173,3.17500000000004,153.697183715));
#600=LINE('',#599,#598);
#601=CARTESIAN_POINT('',(8.00659451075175,3.17499999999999,-134.647183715));
#602=VERTEX_POINT('',#601);
#603=EDGE_CURVE('E213',#44,#602,#600,.F.);
#604=ORIENTED_EDGE('',*,*,#603,.T.);
#605=CARTESIAN_POINT('',(8.00659451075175,3.17499999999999,-134.647183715));
#606=CARTESIAN_POINT('',(8.00657879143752,3.17501205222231,-134.561169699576));
#607=CARTESIAN_POINT('',(8.00798019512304,3.17150498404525,-134.475164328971));
#608=CARTESIAN_POINT('',(8.01350001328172,3.15754665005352,-134.303833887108));
#609=CARTESIAN_POINT('',(8.01761754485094,3.14709764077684,-134.218508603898));
#610=CARTESIAN_POINT('',(8.02843384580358,3.11939719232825,-134.049436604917));
#611=CARTESIAN_POINT('',(8.03512366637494,3.10216933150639,-133.965685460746));
#612=CARTESIAN_POINT('',(8.05086033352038,3.06109615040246,-133.800068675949));
#613=CARTESIAN_POINT('',(8.05990729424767,3.03725050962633,-133.718203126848));
#614=CARTESIAN_POINT('',(8.0901683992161,2.956132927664,-133.476403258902));
#615=CARTESIAN_POINT('',(8.11452302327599,2.88923159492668,-133.319972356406));
#616=CARTESIAN_POINT('',(8.16883258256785,2.73189398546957,-133.02050825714));
#617=CARTESIAN_POINT('',(8.19879191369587,2.64143921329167,-132.877485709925));
#618=CARTESIAN_POINT('',(8.26253332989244,2.43492887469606,-132.602037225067));
#619=CARTESIAN_POINT('',(8.29642486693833,2.3179329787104,-132.470340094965));
#620=CARTESIAN_POINT('',(8.36329714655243,2.06366320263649,-132.227929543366));
#621=CARTESIAN_POINT('',(8.396277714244,1.92638546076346,-132.117220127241));
#622=CARTESIAN_POINT('',(8.45891569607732,1.62990461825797,-131.916412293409));
#623=CARTESIAN_POINT('',(8.48842893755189,1.47013078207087,-131.827107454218));
#624=CARTESIAN_POINT('',(8.53948707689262,1.13655272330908,-131.676949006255));
#625=CARTESIAN_POINT('',(8.56103485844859,0.962753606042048,-131.616085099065));
#626=CARTESIAN_POINT('',(8.59295493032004,0.613765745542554,-131.52709172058));
#627=CARTESIAN_POINT('',(8.60375681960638,0.43893894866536,-131.497699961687));
#628=CARTESIAN_POINT('',(8.61450719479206,0.0865198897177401,-131.468445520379));
#629=CARTESIAN_POINT('',(8.61445889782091,-0.0910715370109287,-131.468574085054));
#630=CARTESIAN_POINT('',(8.60379005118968,-0.434944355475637,-131.497612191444));
#631=CARTESIAN_POINT('',(8.59367530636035,-0.601360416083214,-131.525144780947));
#632=CARTESIAN_POINT('',(8.56466915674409,-0.927017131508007,-131.605898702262));
#633=CARTESIAN_POINT('',(8.5457772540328,-1.08625737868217,-131.659121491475));
#634=CARTESIAN_POINT('',(8.50075667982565,-1.39575977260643,-131.790410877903));
#635=CARTESIAN_POINT('',(8.47452782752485,-1.54585984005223,-131.868823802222));
#636=CARTESIAN_POINT('',(8.41749996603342,-1.83113878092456,-132.047962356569));
#637=CARTESIAN_POINT('',(8.38669950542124,-1.96631289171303,-132.148695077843));
#638=CARTESIAN_POINT('',(8.32165508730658,-2.22602120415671,-132.376298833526));
#639=CARTESIAN_POINT('',(8.28731490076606,-2.3495191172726,-132.504327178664));
#640=CARTESIAN_POINT('',(8.22046423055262,-2.57368622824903,-132.779485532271));
#641=CARTESIAN_POINT('',(8.18795444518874,-2.67434675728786,-132.926622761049));
#642=CARTESIAN_POINT('',(8.12783577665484,-2.85192851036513,-133.23999905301));
#643=CARTESIAN_POINT('',(8.10034614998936,-2.92829789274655,-133.406578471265));
#644=CARTESIAN_POINT('',(8.06616055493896,-3.02064378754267,-133.664975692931));
#645=CARTESIAN_POINT('',(8.05594153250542,-3.04772112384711,-133.752510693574));
#646=CARTESIAN_POINT('',(8.03818255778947,-3.09425676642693,-133.929837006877));
#647=CARTESIAN_POINT('',(8.03064139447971,-3.11371851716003,-134.019627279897));
#648=CARTESIAN_POINT('',(8.0186572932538,-3.144454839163,-134.198742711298));
#649=CARTESIAN_POINT('',(8.01414947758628,-3.15590108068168,-134.288034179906));
#650=CARTESIAN_POINT('',(8.00811024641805,-3.17117692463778,-134.467274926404));
#651=CARTESIAN_POINT('',(8.0065758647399,-3.17501411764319,-134.557223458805));
#652=CARTESIAN_POINT('',(8.00659451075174,-3.17500000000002,-134.647183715));
#653=B_SPLINE_CURVE_WITH_KNOTS('',3,(#605,#606,#607,#608,#609,#610,#611,#612,#613,#614,#615,
#616,#617,#618,#619,#620,#621,#622,#623,#624,#625,#626,#627,#628,#629,#630,#631,#632,#633,#634,
#635,#636,#637,#638,#639,#640,#641,#642,#643,#644,#645,#646,#647,#648,#649,#650,#651,#652),
.UNSPECIFIED.,.F.,.F.,(4,2,2,2,2,2,2,2,2,2,2,2,2,2,2,2,2,2,2,2,2,2,2,4),(0.,0.257944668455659,
0.515805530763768,0.772777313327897,1.0297615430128,1.54284702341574,2.05633662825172,
2.59210103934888,3.1279675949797,3.68138042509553,4.23459270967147,4.76467407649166,
5.29459827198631,5.79917501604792,6.30378038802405,6.81564369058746,7.32766985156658,
7.86869704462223,8.40992926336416,8.96269988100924,9.23897231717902,9.51511965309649,
9.78515512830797,10.0549210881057),.UNSPECIFIED.);
#654=CARTESIAN_POINT('',(8.00659451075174,-3.17500000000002,-134.647183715));
#655=VERTEX_POINT('',#654);
#656=EDGE_CURVE('E200',#602,#655,#653,.T.);
#657=ORIENTED_EDGE('',*,*,#656,.T.);
#658=DIRECTION('',(0.,0.,-1.));
#659=VECTOR('',#658,1.);
#660=CARTESIAN_POINT('',(8.00659451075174,-3.17500000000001,153.697183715));
#661=LINE('',#660,#659);
#662=EDGE_CURVE('E355',#655,#62,#661,.T.);
#663=ORIENTED_EDGE('',*,*,#662,.T.);
#664=ORIENTED_EDGE('',*,*,#75,.F.);
#665=DIRECTION('',(0.,0.,-1.));
#666=VECTOR('',#665,1.);
#667=CARTESIAN_POINT('',(-8.00659451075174,-3.17500000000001,153.697183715));
#668=LINE('',#667,#666);
#669=EDGE_CURVE('E49',#72,#585,#668,.F.);
#670=ORIENTED_EDGE('',*,*,#669,.T.);
#671=EDGE_LOOP('',(#589,#595,#596,#604,#657,#663,#664,#670));
#672=FACE_BOUND('',#671,.T.);
#673=ADVANCED_FACE('F214',(#534,#672),#381,.F.);
#674=CARTESIAN_POINT('',(0.,0.,153.697183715));
#675=DIRECTION('',(0.,0.,1.));
#676=DIRECTION('',(1.,0.,0.));
#677=AXIS2_PLACEMENT_3D('',#674,#675,#676);
#678=PLANE('',#677);
#679=DIRECTION('',(1.,0.,0.));
#680=VECTOR('',#679,1.);
#681=CARTESIAN_POINT('',(-9.525,3.17499999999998,153.697183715));
#682=LINE('',#681,#680);
#683=EDGE_CURVE('E298',#528,#91,#682,.T.);
#684=ORIENTED_EDGE('',*,*,#683,.T.);
#685=ORIENTED_EDGE('',*,*,#94,.T.);
#686=EDGE_CURVE('E297',#93,#389,#682,.T.);
#687=ORIENTED_EDGE('',*,*,#686,.T.);
#688=ORIENTED_EDGE('',*,*,#531,.F.);
#689=EDGE_LOOP('',(#684,#685,#687,#688));
#690=FACE_BOUND('',#689,.T.);
#691=ADVANCED_FACE('F219',(#690),#678,.T.);
#692=DIRECTION('',(1.,0.,0.));
#693=VECTOR('',#692,1.);
#694=CARTESIAN_POINT('',(-9.525,-3.17500000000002,153.697183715));
#695=LINE('',#694,#693);
#696=EDGE_CURVE('E324',#166,#450,#695,.T.);
#697=ORIENTED_EDGE('',*,*,#696,.F.);
#698=ORIENTED_EDGE('',*,*,#167,.T.);
#699=EDGE_CURVE('E325',#459,#162,#695,.T.);
#700=ORIENTED_EDGE('',*,*,#699,.F.);
#701=ORIENTED_EDGE('',*,*,#460,.F.);
#702=EDGE_LOOP('',(#697,#698,#700,#701));
#703=FACE_BOUND('',#702,.T.);
#704=ADVANCED_FACE('F366',(#703),#678,.T.);
#705=CARTESIAN_POINT('',(-9.525,-3.17500000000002,153.697183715));
#706=DIRECTION('',(0.,-1.,0.));
#707=DIRECTION('',(0.,0.,-1.));
#708=AXIS2_PLACEMENT_3D('',#705,#706,#707);
#709=PLANE('',#708);
#710=DIRECTION('',(1.,0.,0.));
#711=VECTOR('',#710,1.);
#712=CARTESIAN_POINT('',(-9.525,-3.17500000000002,134.647183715));
#713=LINE('',#712,#711);
#714=EDGE_CURVE('E321',#467,#154,#713,.T.);
#715=ORIENTED_EDGE('',*,*,#714,.F.);
#716=ORIENTED_EDGE('',*,*,#468,.T.);
#717=ORIENTED_EDGE('',*,*,#699,.T.);
#718=ORIENTED_EDGE('',*,*,#163,.F.);
#719=EDGE_LOOP('',(#715,#716,#717,#718));
#720=FACE_BOUND('',#719,.T.);
#721=ADVANCED_FACE('F244',(#720),#709,.F.);
#722=CARTESIAN_POINT('',(-9.525,0.,134.647183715));
#723=DIRECTION('',(1.,0.,0.));
#724=DIRECTION('',(0.,0.,-1.));
#725=AXIS2_PLACEMENT_3D('',#722,#723,#724);
#726=CYLINDRICAL_SURFACE('',#725,3.175);
#727=DIRECTION('',(1.,0.,0.));
#728=VECTOR('',#727,1.);
#729=CARTESIAN_POINT('',(-9.525,3.17499999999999,134.647183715));
#730=LINE('',#729,#728);
#731=EDGE_CURVE('E313',#520,#101,#730,.T.);
#732=ORIENTED_EDGE('',*,*,#731,.F.);
#733=ORIENTED_EDGE('',*,*,#521,.T.);
#734=ORIENTED_EDGE('',*,*,#714,.T.);
#735=ORIENTED_EDGE('',*,*,#155,.F.);
#736=EDGE_LOOP('',(#732,#733,#734,#735));
#737=FACE_BOUND('',#736,.T.);
#738=ADVANCED_FACE('F241',(#737),#726,.F.);
#739=CARTESIAN_POINT('',(-9.525,3.17499999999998,153.697183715));
#740=DIRECTION('',(0.,1.,0.));
#741=DIRECTION('',(0.,0.,1.));
#742=AXIS2_PLACEMENT_3D('',#739,#740,#741);
#743=PLANE('',#742);
#744=ORIENTED_EDGE('',*,*,#683,.F.);
#745=ORIENTED_EDGE('',*,*,#529,.T.);
#746=ORIENTED_EDGE('',*,*,#731,.T.);
#747=ORIENTED_EDGE('',*,*,#102,.F.);
#748=EDGE_LOOP('',(#744,#745,#746,#747));
#749=FACE_BOUND('',#748,.T.);
#750=ADVANCED_FACE('F221',(#749),#743,.F.);
#751=EDGE_CURVE('E306',#227,#387,#730,.T.);
#752=ORIENTED_EDGE('',*,*,#751,.T.);
#753=ORIENTED_EDGE('',*,*,#390,.T.);
#754=ORIENTED_EDGE('',*,*,#686,.F.);
#755=ORIENTED_EDGE('',*,*,#234,.F.);
#756=EDGE_LOOP('',(#752,#753,#754,#755));
#757=FACE_BOUND('',#756,.T.);
#758=ADVANCED_FACE('F305',(#757),#743,.F.);
#759=EDGE_CURVE('E317',#174,#442,#713,.T.);
#760=ORIENTED_EDGE('',*,*,#759,.T.);
#761=ORIENTED_EDGE('',*,*,#443,.T.);
#762=ORIENTED_EDGE('',*,*,#751,.F.);
#763=ORIENTED_EDGE('',*,*,#228,.F.);
#764=EDGE_LOOP('',(#760,#761,#762,#763));
#765=FACE_BOUND('',#764,.T.);
#766=ADVANCED_FACE('F246',(#765),#726,.F.);
#767=ORIENTED_EDGE('',*,*,#696,.T.);
#768=ORIENTED_EDGE('',*,*,#451,.T.);
#769=ORIENTED_EDGE('',*,*,#759,.F.);
#770=ORIENTED_EDGE('',*,*,#175,.F.);
#771=EDGE_LOOP('',(#767,#768,#769,#770));
#772=FACE_BOUND('',#771,.T.);
#773=ADVANCED_FACE('F247',(#772),#709,.F.);
#774=CARTESIAN_POINT('',(-9.525,0.,-134.647183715));
#775=DIRECTION('',(1.,0.,0.));
#776=DIRECTION('',(0.,0.,-1.));
#777=AXIS2_PLACEMENT_3D('',#774,#775,#776);
#778=CYLINDRICAL_SURFACE('',#777,3.175);
#779=ORIENTED_EDGE('',*,*,#306,.T.);
#780=DIRECTION('',(1.,0.,0.));
#781=VECTOR('',#780,1.);
#782=CARTESIAN_POINT('',(-9.525,-3.17500000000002,-134.647183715));
#783=LINE('',#782,#781);
#784=EDGE_CURVE('E64',#655,#252,#783,.T.);
#785=ORIENTED_EDGE('',*,*,#784,.F.);
#786=ORIENTED_EDGE('',*,*,#656,.F.);
#787=DIRECTION('',(1.,0.,0.));
#788=VECTOR('',#787,1.);
#789=CARTESIAN_POINT('',(-9.525,3.17499999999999,-134.647183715));
#790=LINE('',#789,#788);
#791=EDGE_CURVE('E346',#602,#305,#790,.T.);
#792=ORIENTED_EDGE('',*,*,#791,.T.);
#793=EDGE_LOOP('',(#779,#785,#786,#792));
#794=FACE_BOUND('',#793,.T.);
#795=ADVANCED_FACE('F193',(#794),#778,.F.);
#796=CARTESIAN_POINT('',(-9.525,-3.17500000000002,-153.697183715));
#797=DIRECTION('',(0.,1.,0.));
#798=DIRECTION('',(0.,0.,1.));
#799=AXIS2_PLACEMENT_3D('',#796,#797,#798);
#800=PLANE('',#799);
#801=ORIENTED_EDGE('',*,*,#253,.T.);
#802=ORIENTED_EDGE('',*,*,#65,.F.);
#803=ORIENTED_EDGE('',*,*,#662,.F.);
#804=ORIENTED_EDGE('',*,*,#784,.T.);
#805=EDGE_LOOP('',(#801,#802,#803,#804));
#806=FACE_BOUND('',#805,.T.);
#807=ADVANCED_FACE('F194',(#806),#800,.T.);
#808=CARTESIAN_POINT('',(-9.525,3.17499999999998,-153.697183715));
#809=DIRECTION('',(0.,-1.,0.));
#810=DIRECTION('',(0.,0.,-1.));
#811=AXIS2_PLACEMENT_3D('',#808,#809,#810);
#812=PLANE('',#811);
#813=ORIENTED_EDGE('',*,*,#312,.T.);
#814=ORIENTED_EDGE('',*,*,#791,.F.);
#815=ORIENTED_EDGE('',*,*,#603,.F.);
#816=ORIENTED_EDGE('',*,*,#45,.T.);
#817=EDGE_LOOP('',(#813,#814,#815,#816));
#818=FACE_BOUND('',#817,.T.);
#819=ADVANCED_FACE('F353',(#818),#812,.T.);
#820=ORIENTED_EDGE('',*,*,#321,.T.);
#821=ORIENTED_EDGE('',*,*,#32,.T.);
#822=ORIENTED_EDGE('',*,*,#594,.F.);
#823=EDGE_CURVE('E56',#320,#587,#790,.T.);
#824=ORIENTED_EDGE('',*,*,#823,.F.);
#825=EDGE_LOOP('',(#820,#821,#822,#824));
#826=FACE_BOUND('',#825,.T.);
#827=ADVANCED_FACE('F195',(#826),#812,.T.);
#828=ORIENTED_EDGE('',*,*,#244,.T.);
#829=EDGE_CURVE('E157',#243,#585,#783,.T.);
#830=ORIENTED_EDGE('',*,*,#829,.T.);
#831=ORIENTED_EDGE('',*,*,#669,.F.);
#832=ORIENTED_EDGE('',*,*,#73,.F.);
#833=EDGE_LOOP('',(#828,#830,#831,#832));
#834=FACE_BOUND('',#833,.T.);
#835=ADVANCED_FACE('F156',(#834),#800,.T.);
#836=ORIENTED_EDGE('',*,*,#372,.T.);
#837=ORIENTED_EDGE('',*,*,#823,.T.);
#838=ORIENTED_EDGE('',*,*,#588,.F.);
#839=ORIENTED_EDGE('',*,*,#829,.F.);
#840=EDGE_LOOP('',(#836,#837,#838,#839));
#841=FACE_BOUND('',#840,.T.);
#842=ADVANCED_FACE('F168',(#841),#778,.F.);
#843=CLOSED_SHELL('',(#56,#79,#376,#673,#691,#704,#721,#738,#750,#758,#766,#773,#795,#807,#819,
#827,#835,#842));
#844=MANIFOLD_SOLID_BREP('B2',#843);
#845=ADVANCED_BREP_SHAPE_REPRESENTATION('',(#18,#844),#14);
#846=SHAPE_DEFINITION_REPRESENTATION(#9,#845);
ENDSEC;
END-ISO-10303-21;
